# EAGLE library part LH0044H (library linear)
OP AMP

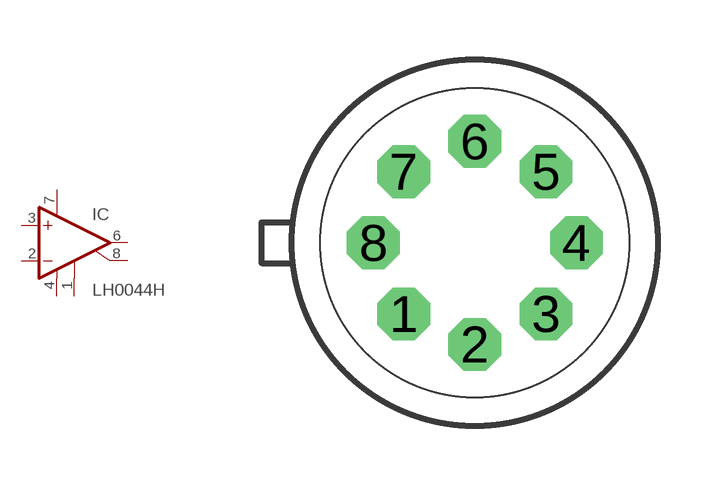
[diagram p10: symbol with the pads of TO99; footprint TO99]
Designator prefix IC

## LH0044H  [TO99]
1  CMP1  pas
2  -IN  in
3  +IN  in
4  V-  pwr
6  OUT  out
7  V+  pwr
8  CMP2  pas

## Footprint TO99 (pad centres in mm)
Metal Can Package
drill 0.813 octagon: 1 -1.778,-1.778; 2 0,-2.54; 3 1.778,-1.778; 4 2.54,0; 5 1.778,1.778; 6 0,2.54; 7 -1.778,1.778; 8 -2.54,0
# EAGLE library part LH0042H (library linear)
OP AMP

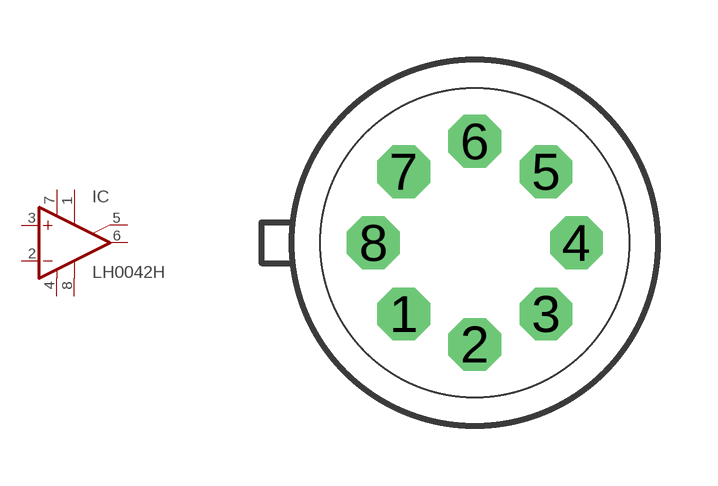
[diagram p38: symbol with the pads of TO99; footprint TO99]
Designator prefix IC

## LH0042H  [TO99]
1  ON1  pas
2  -IN  in
3  +IN  in
4  V-  pwr
5  ON2  pas
6  OUT  out
7  V+  pwr
8  OPT  pas

## Footprint TO99 (pad centres in mm)
Metal Can Package
drill 0.813 octagon: 1 -1.778,-1.778; 2 0,-2.54; 3 1.778,-1.778; 4 2.54,0; 5 1.778,1.778; 6 0,2.54; 7 -1.778,1.778; 8 -2.54,0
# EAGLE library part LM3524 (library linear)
Regulating Pulse Width Modulator LM2524D/LM3524D Source: http://cache.national.com/ds/LM/LM2524D.pdf

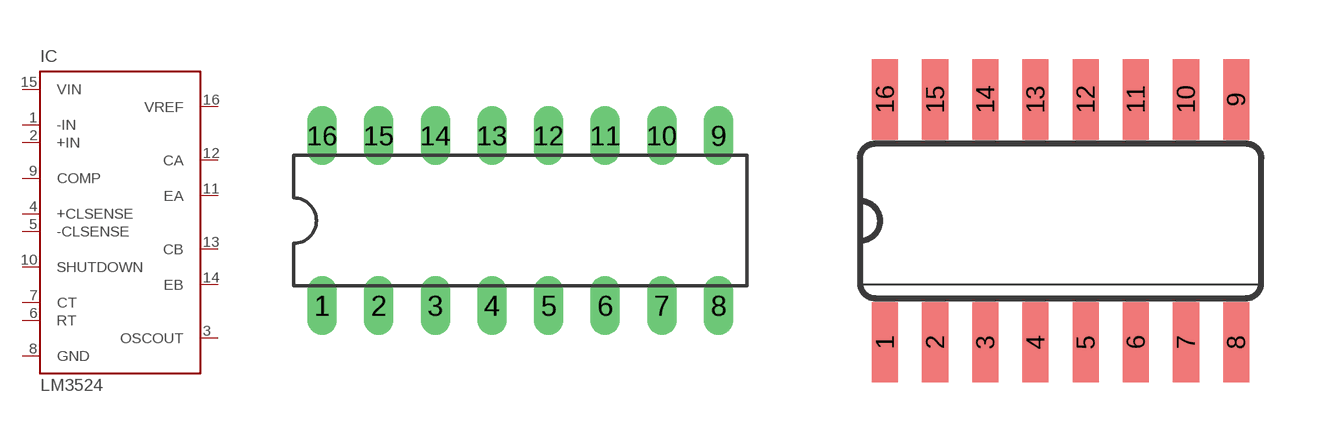
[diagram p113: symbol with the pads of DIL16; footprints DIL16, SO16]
Designator prefix IC

## LM3524N  [DIL16]
1  -IN  in
2  +IN  in
3  OSCOUT  out
4  +CLSENSE  in
5  -CLSENSE  in
6  RT  in
7  CT  in
8  GND  pwr
9  COMP  in
10  SHUTDOWN  in
11  EA  pas
12  CA  pas
13  CB  pas
14  EB  pas
15  VIN  in
16  VREF  pas

## LM3524D  [SO16]
Pads as for DIL16

## Footprint DIL16 (pad centres in mm)
Dual In Line Package
drill 0.813 long: 1 -8.89,-3.81; 2 -6.35,-3.81; 3 -3.81,-3.81; 4 -1.27,-3.81; 5 1.27,-3.81; 6 3.81,-3.81; 7 6.35,-3.81; 8 8.89,-3.81; 9 8.89,3.81; 10 6.35,3.81; 11 3.81,3.81; 12 1.27,3.81; 13 -1.27,3.81; 14 -3.81,3.81; 15 -6.35,3.81; 16 -8.89,3.81

## Footprint SO16 (pad centres in mm)
Small Outline Package 16
smd 0.66 x 2.032: 1 -4.445,-3.073; 2 -3.175,-3.073; 3 -1.905,-3.073; 4 -0.635,-3.073; 5 0.635,-3.073; 6 1.905,-3.073; 7 3.175,-3.073; 8 4.445,-3.073; 9 4.445,3.073; 10 3.175,3.073; 11 1.905,3.073; 12 0.635,3.073; 13 -0.635,3.073; 14 -1.905,3.073; 15 -3.175,3.073; 16 -4.445,3.073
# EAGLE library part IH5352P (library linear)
CMOS SWITCH

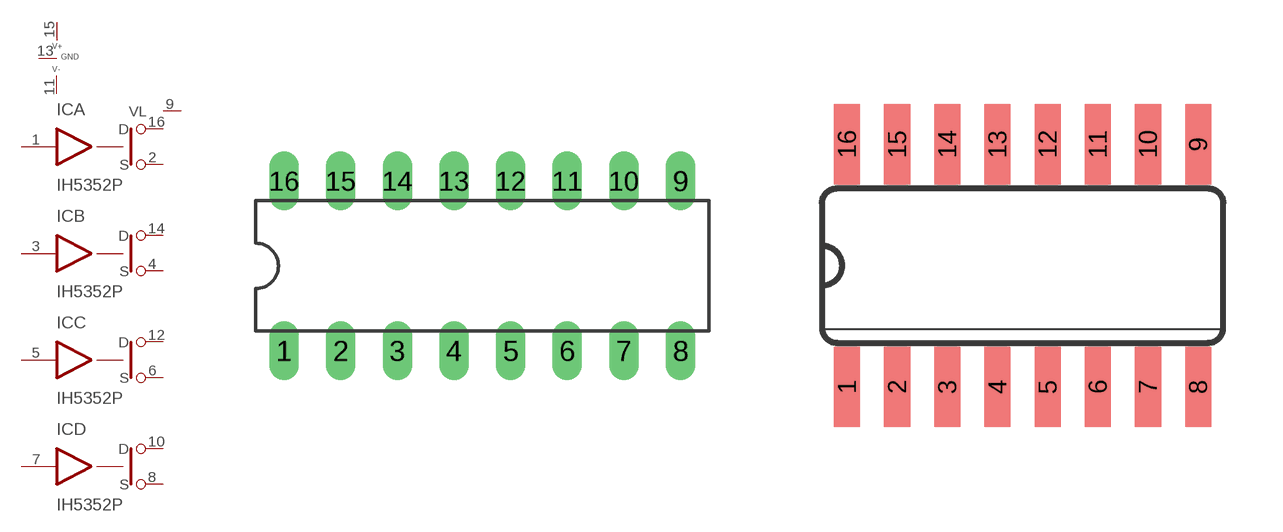
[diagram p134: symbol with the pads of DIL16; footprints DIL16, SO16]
Designator prefix IC; gates A=SWSPSTNI B=SWSPSTNI C=SWSPSTNI D=SWSPSTNI P=PWR+-GSS VL=VL_PIN

## IH5352PP  [DIL16]
1  A:IN  in
2  A:S
3  B:IN  in
4  B:S
5  C:IN  in
6  C:S
7  D:IN  in
8  D:S
9  VL:VL  in
10  D:D
11  P:V-  pwr
12  C:D
13  P:GND  pwr
14  B:D
15  P:V+  pwr
16  A:D

## IH5352PD  [SO16]
Pads as for DIL16

## Footprint DIL16 (pad centres in mm)
Dual In Line Package
drill 0.813 long: 1 -8.89,-3.81; 2 -6.35,-3.81; 3 -3.81,-3.81; 4 -1.27,-3.81; 5 1.27,-3.81; 6 3.81,-3.81; 7 6.35,-3.81; 8 8.89,-3.81; 9 8.89,3.81; 10 6.35,3.81; 11 3.81,3.81; 12 1.27,3.81; 13 -1.27,3.81; 14 -3.81,3.81; 15 -6.35,3.81; 16 -8.89,3.81

## Footprint SO16 (pad centres in mm)
Small Outline Package 16
smd 0.66 x 2.032: 1 -4.445,-3.073; 2 -3.175,-3.073; 3 -1.905,-3.073; 4 -0.635,-3.073; 5 0.635,-3.073; 6 1.905,-3.073; 7 3.175,-3.073; 8 4.445,-3.073; 9 4.445,3.073; 10 3.175,3.073; 11 1.905,3.073; 12 0.635,3.073; 13 -0.635,3.073; 14 -1.905,3.073; 15 -3.175,3.073; 16 -4.445,3.073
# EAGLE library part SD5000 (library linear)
DMOS SWITCH

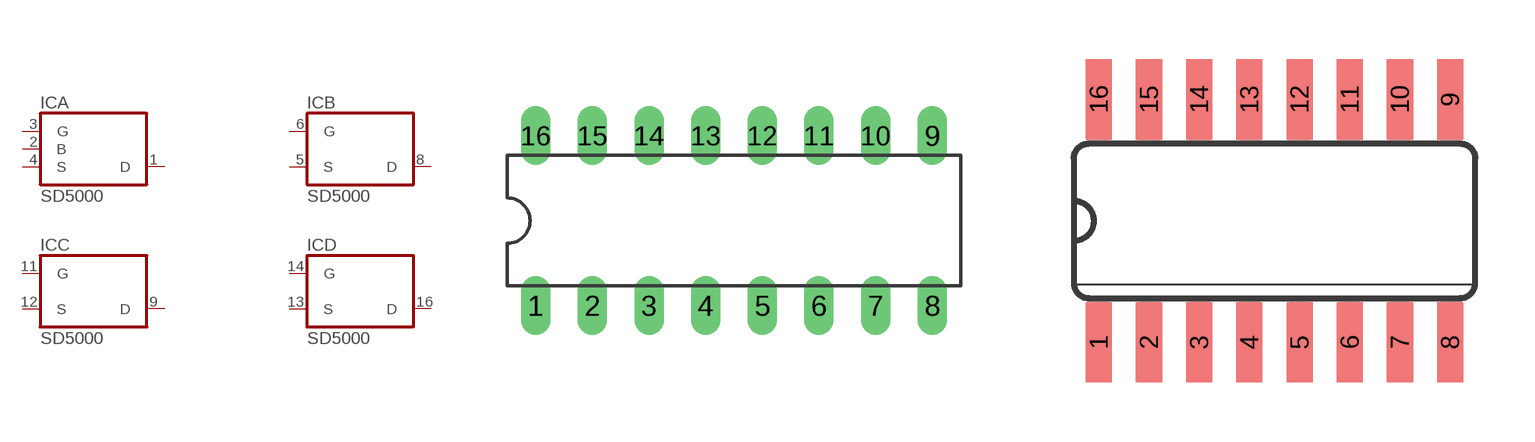
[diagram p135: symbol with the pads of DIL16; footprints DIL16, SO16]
Designator prefix IC; gates A=SD5000 P=SD5000/B B=SD5000 C=SD5000 D=SD5000

## SD5000N  [DIL16]
1  A:D  out
2  P:B  pwr
3  A:G  in
4  A:S  in
5  B:S  in
6  B:G  in
8  B:D  out
9  C:D  out
11  C:G  in
12  C:S  in
13  D:S  in
14  D:G  in
16  D:D  out

## SD5000D  [SO16]
Pads as for DIL16

## Footprint DIL16 (pad centres in mm)
Dual In Line Package
drill 0.813 long: 1 -8.89,-3.81; 2 -6.35,-3.81; 3 -3.81,-3.81; 4 -1.27,-3.81; 5 1.27,-3.81; 6 3.81,-3.81; 7 6.35,-3.81; 8 8.89,-3.81; 9 8.89,3.81; 10 6.35,3.81; 11 3.81,3.81; 12 1.27,3.81; 13 -1.27,3.81; 14 -3.81,3.81; 15 -6.35,3.81; 16 -8.89,3.81

## Footprint SO16 (pad centres in mm)
Small Outline Package 16
smd 0.66 x 2.032: 1 -4.445,-3.073; 2 -3.175,-3.073; 3 -1.905,-3.073; 4 -0.635,-3.073; 5 0.635,-3.073; 6 1.905,-3.073; 7 3.175,-3.073; 8 4.445,-3.073; 9 4.445,3.073; 10 3.175,3.073; 11 1.905,3.073; 12 0.635,3.073; 13 -0.635,3.073; 14 -1.905,3.073; 15 -3.175,3.073; 16 -4.445,3.073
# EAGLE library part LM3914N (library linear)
LED DRIVER senses analog voltage levels and drives 10 LEDs

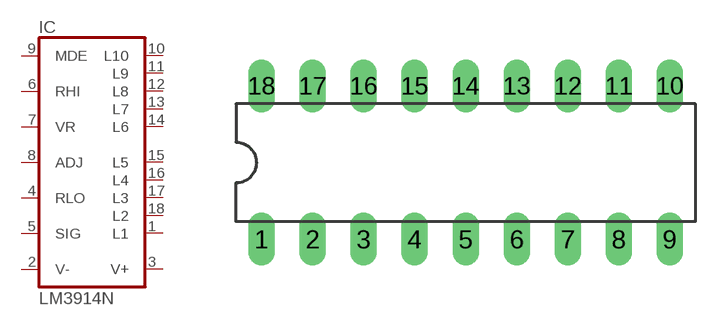
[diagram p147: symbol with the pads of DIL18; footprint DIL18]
Designator prefix IC

## LM3914N  [DIL18]
1  L1  out
2  V-  pwr
3  V+  pwr
4  RLO  in
5  SIG  in
6  RHI  in
7  VR  out
8  ADJ  in
9  MDE  in
10  L10  out
11  L9  out
12  L8  out
13  L7  out
14  L6  out
15  L5  out
16  L4  out
17  L3  out
18  L2  out

## Footprint DIL18 (pad centres in mm)
Dual In Line Package
drill 0.813 long: 1 -10.16,-3.81; 2 -7.62,-3.81; 3 -5.08,-3.81; 4 -2.54,-3.81; 5 0,-3.81; 6 2.54,-3.81; 7 5.08,-3.81; 8 7.62,-3.81; 9 10.16,-3.81; 10 10.16,3.81; 11 7.62,3.81; 12 5.08,3.81; 13 2.54,3.81; 14 0,3.81; 15 -2.54,3.81; 16 -5.08,3.81; 17 -7.62,3.81; 18 -10.16,3.81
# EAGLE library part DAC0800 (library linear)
8-bit DIGITAL/ANALOG CONVERTER

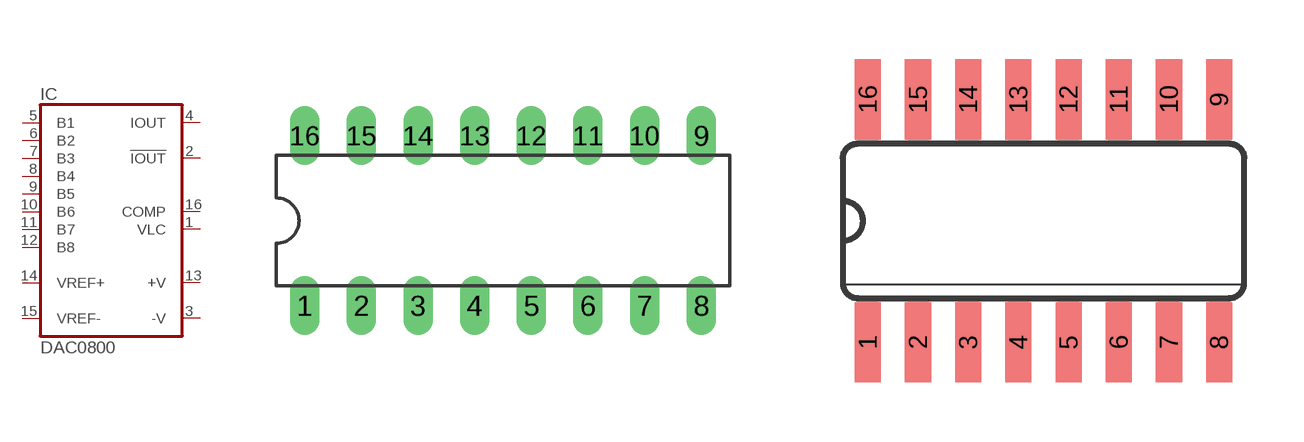
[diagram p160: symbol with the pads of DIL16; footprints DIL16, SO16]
Designator prefix IC

## DAC0800N  [DIL16]
1  VLC  in
2  !IOUT  out
3  -V  pwr
4  IOUT  out
5  B1  in
6  B2  in
7  B3  in
8  B4  in
9  B5  in
10  B6  in
11  B7  in
12  B8  in
13  +V  pwr
14  VREF+  in
15  VREF-  in
16  COMP  in

## DAC0800D  [SO16]
Pads as for DIL16

## Footprint DIL16 (pad centres in mm)
Dual In Line Package
drill 0.813 long: 1 -8.89,-3.81; 2 -6.35,-3.81; 3 -3.81,-3.81; 4 -1.27,-3.81; 5 1.27,-3.81; 6 3.81,-3.81; 7 6.35,-3.81; 8 8.89,-3.81; 9 8.89,3.81; 10 6.35,3.81; 11 3.81,3.81; 12 1.27,3.81; 13 -1.27,3.81; 14 -3.81,3.81; 15 -6.35,3.81; 16 -8.89,3.81

## Footprint SO16 (pad centres in mm)
Small Outline Package 16
smd 0.66 x 2.032: 1 -4.445,-3.073; 2 -3.175,-3.073; 3 -1.905,-3.073; 4 -0.635,-3.073; 5 0.635,-3.073; 6 1.905,-3.073; 7 3.175,-3.073; 8 4.445,-3.073; 9 4.445,3.073; 10 3.175,3.073; 11 1.905,3.073; 12 0.635,3.073; 13 -0.635,3.073; 14 -1.905,3.073; 15 -3.175,3.073; 16 -4.445,3.073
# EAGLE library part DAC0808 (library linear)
8-bit DIGITAL/ANALOG CONVERTER Source: http://www.national.com/ds/DA/DAC0808.pdf

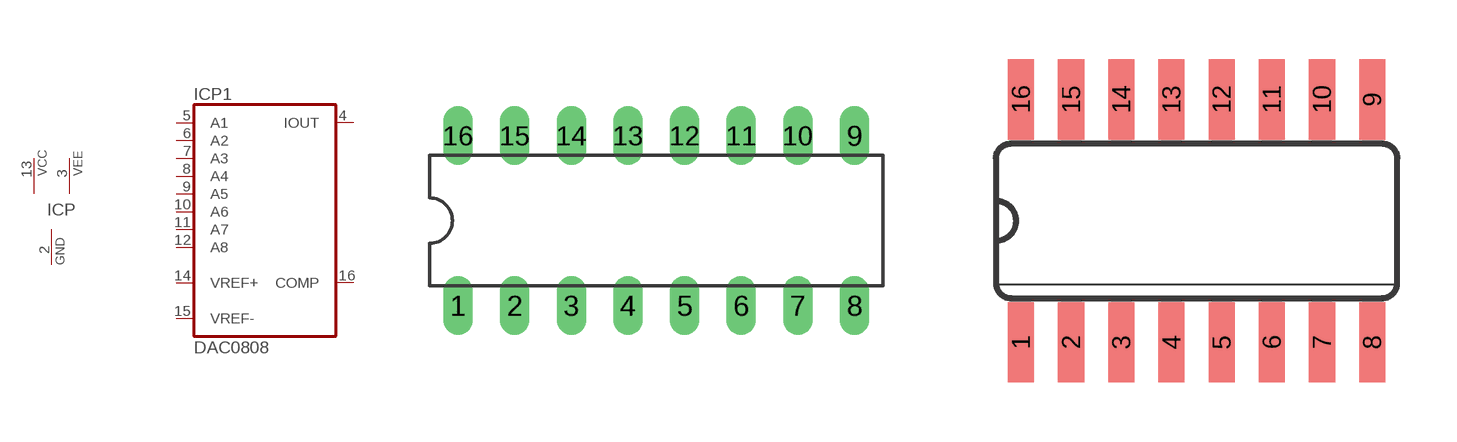
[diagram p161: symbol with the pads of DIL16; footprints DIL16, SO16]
Designator prefix IC; gates P=2PWRGND P1=DAC0808

## DAC0808N  [DIL16]
2  P:GND  pwr
3  P:VEE  pwr
4  P1:IOUT  out
5  P1:A1  in
6  P1:A2  in
7  P1:A3  in
8  P1:A4  in
9  P1:A5  in
10  P1:A6  in
11  P1:A7  in
12  P1:A8  in
13  P:VCC  pwr
14  P1:VREF+  in
15  P1:VREF-  in
16  P1:COMP  in

## DAC0808D  [SO16]
1  P:VCC  pwr
2  P1:VREF+  in
3  P1:VREF-  in
4  P1:COMP  in
6  P:GND  pwr
7  P:VEE  pwr
8  P1:IOUT  out
9  P1:A1  in
10  P1:A2  in
11  P1:A3  in
12  P1:A4  in
13  P1:A5  in
14  P1:A6  in
15  P1:A7  in
16  P1:A8  in

## Footprint DIL16 (pad centres in mm)
Dual In Line Package
drill 0.813 long: 1 -8.89,-3.81; 2 -6.35,-3.81; 3 -3.81,-3.81; 4 -1.27,-3.81; 5 1.27,-3.81; 6 3.81,-3.81; 7 6.35,-3.81; 8 8.89,-3.81; 9 8.89,3.81; 10 6.35,3.81; 11 3.81,3.81; 12 1.27,3.81; 13 -1.27,3.81; 14 -3.81,3.81; 15 -6.35,3.81; 16 -8.89,3.81

## Footprint SO16 (pad centres in mm)
Small Outline Package 16
smd 0.66 x 2.032: 1 -4.445,-3.073; 2 -3.175,-3.073; 3 -1.905,-3.073; 4 -0.635,-3.073; 5 0.635,-3.073; 6 1.905,-3.073; 7 3.175,-3.073; 8 4.445,-3.073; 9 4.445,3.073; 10 3.175,3.073; 11 1.905,3.073; 12 0.635,3.073; 13 -0.635,3.073; 14 -1.905,3.073; 15 -3.175,3.073; 16 -4.445,3.073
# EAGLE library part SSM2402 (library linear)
ANALOG SWITCH

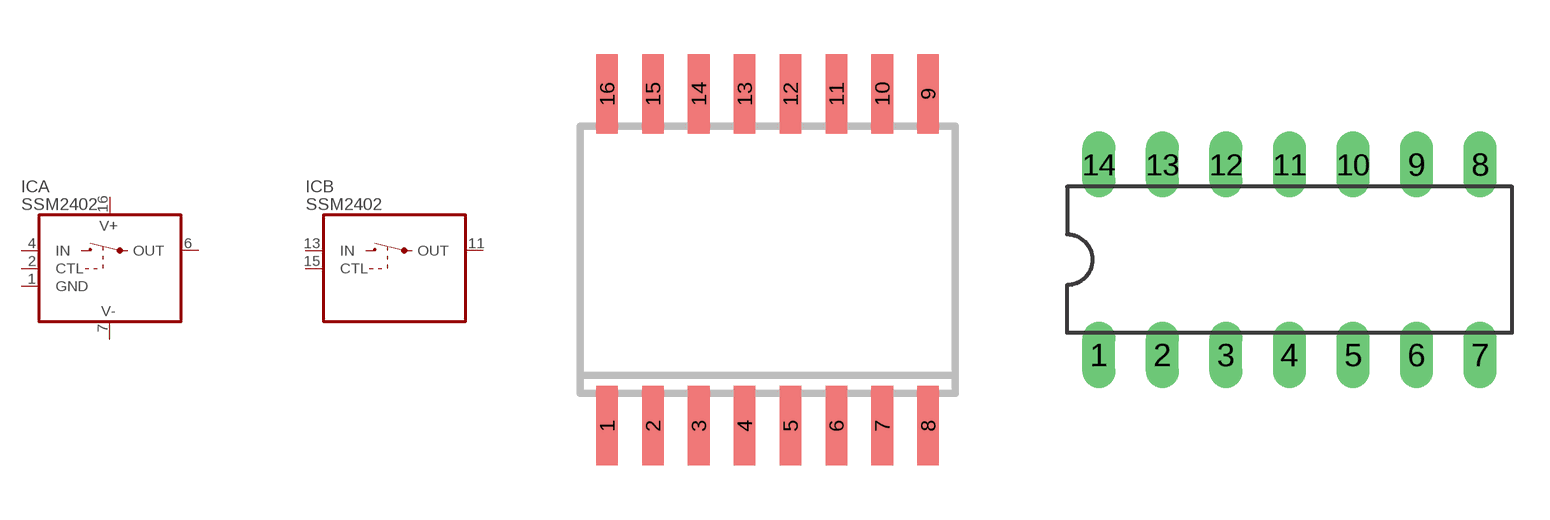
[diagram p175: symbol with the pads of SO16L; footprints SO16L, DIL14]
Designator prefix IC; gates A=SSM2402 B=SSM2402 P=PWR+-GR

## SSM2402S  [SO16L]
1  P:GND  pwr
2  A:CTL  in
4  A:IN  in
6  A:OUT  out
7  P:V-  pwr
11  B:OUT  out
13  B:IN  in
15  B:CTL  in
16  P:V+  pwr

## SSM2402P  [DIL14]
1  P:GND  pwr
2  A:CTL  in
4  A:IN  in
6  A:OUT  out
7  P:V-  pwr
9  B:OUT  out
11  B:IN  in
13  B:CTL  in
14  P:V+  pwr

## Footprint SO16L (pad centres in mm)
Small Outline Package 16 large
smd 0.6 x 2.2: 1 -4.445,-4.6; 2 -3.175,-4.6; 3 -1.905,-4.6; 4 -0.635,-4.6; 5 0.635,-4.6; 6 1.905,-4.6; 7 3.175,-4.6; 8 4.445,-4.6; 9 4.445,4.6; 10 3.175,4.6; 11 1.905,4.6; 12 0.635,4.6; 13 -0.635,4.6; 14 -1.905,4.6; 15 -3.175,4.6; 16 -4.445,4.6

## Footprint DIL14 (pad centres in mm)
Dual In Line Package
drill 0.813 long: 1 -7.62,-3.81; 2 -5.08,-3.81; 3 -2.54,-3.81; 4 0,-3.81; 5 2.54,-3.81; 6 5.08,-3.81; 7 7.62,-3.81; 8 7.62,3.81; 9 5.08,3.81; 10 2.54,3.81; 11 0,3.81; 12 -2.54,3.81; 13 -5.08,3.81; 14 -7.62,3.81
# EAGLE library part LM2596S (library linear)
STEP-DOWN VOLTAGE REGULATOR

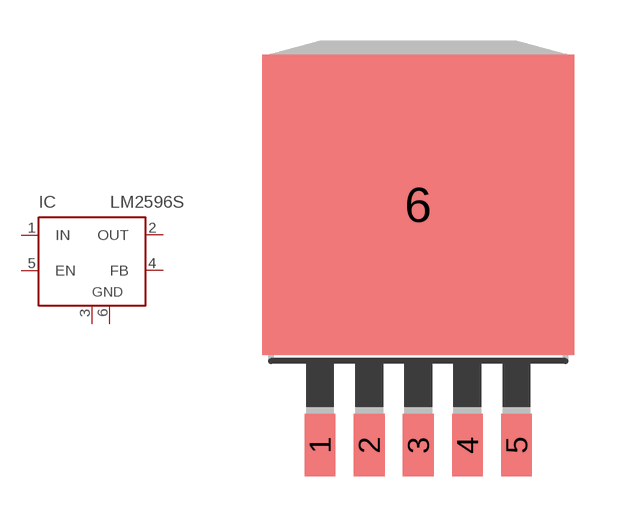
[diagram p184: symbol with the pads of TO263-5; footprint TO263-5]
Designator prefix IC

## LM2596S  [TO263-5]
1  IN  in
2  OUT  out
3  GND  pwr
4  FB  in
5  EN  in
6  GND  pwr

## Footprint TO263-5 (pad centres in mm)
TO-263
smd 1.067 x 2.159: 1 -3.404,-5.791; 2 -1.702,-5.791; 3 0,-5.791; 4 1.702,-5.791; 5 3.404,-5.791
smd 10.8 x 10.41: 6 0,2.54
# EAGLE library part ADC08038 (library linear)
A/D CONVERTER

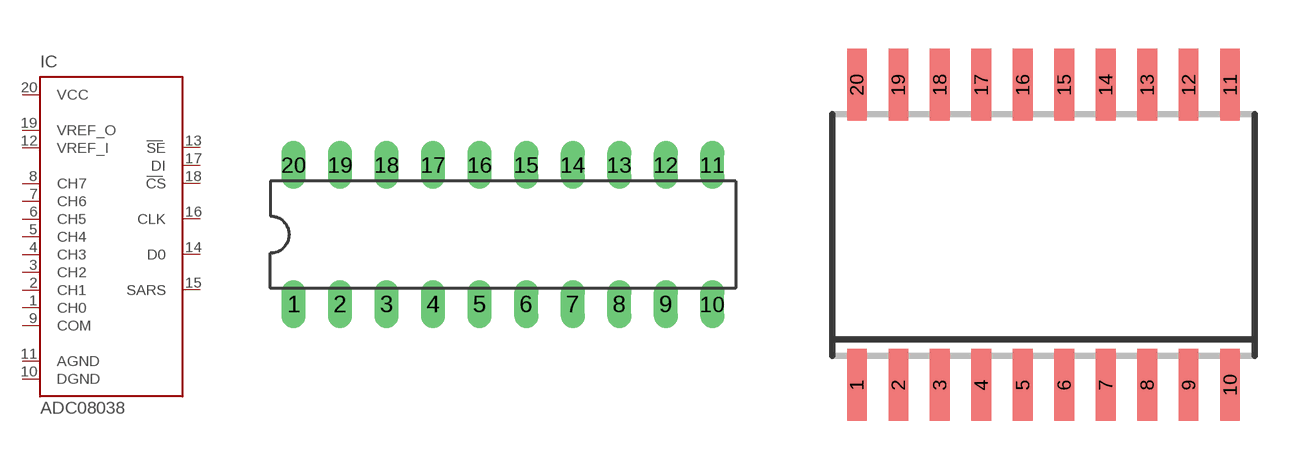
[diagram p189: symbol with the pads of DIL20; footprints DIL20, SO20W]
Designator prefix IC

## ADC08038N  [DIL20]
1  CH0  in
2  CH1  in
3  CH2  in
4  CH3  in
5  CH4  in
6  CH5  in
7  CH6  in
8  CH7  in
9  COM  in
10  DGND  pwr
11  AGND  pwr
12  VREF_I  in
13  SE  in
14  D0  hiz
15  SARS  out
16  CLK  in
17  DI  in
18  CS  in
19  VREF_O  out
20  VCC  pwr

## ADC08038D  [SO20W]
Pads as for DIL20

## Footprint DIL20 (pad centres in mm)
Dual In Line Package
drill 0.813 long: 1 -11.43,-3.81; 2 -8.89,-3.81; 3 -6.35,-3.81; 4 -3.81,-3.81; 5 -1.27,-3.81; 6 1.27,-3.81; 7 3.81,-3.81; 8 6.35,-3.81; 9 8.89,-3.81; 10 11.43,-3.81; 11 11.43,3.81; 12 8.89,3.81; 13 6.35,3.81; 14 3.81,3.81; 15 1.27,3.81; 16 -1.27,3.81; 17 -3.81,3.81; 18 -6.35,3.81; 19 -8.89,3.81; 20 -11.43,3.81

## Footprint SO20W (pad centres in mm)
Small Outline Package 20 wide
smd 0.6 x 2.2: 1 -5.715,-4.6; 2 -4.445,-4.6; 3 -3.175,-4.6; 4 -1.905,-4.6; 5 -0.635,-4.6; 6 0.635,-4.6; 7 1.905,-4.6; 8 3.175,-4.6; 9 4.445,-4.6; 10 5.715,-4.6; 11 5.715,4.6; 12 4.445,4.6; 13 3.175,4.6; 14 1.905,4.6; 15 0.635,4.6; 16 -0.635,4.6; 17 -1.905,4.6; 18 -3.175,4.6; 19 -4.445,4.6; 20 -5.715,4.6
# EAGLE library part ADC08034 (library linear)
A/D CONVERTER

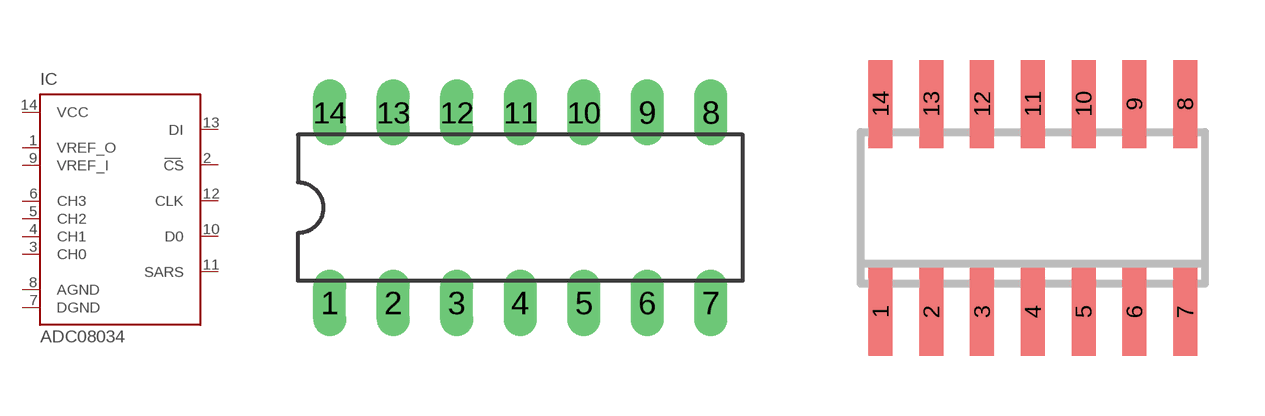
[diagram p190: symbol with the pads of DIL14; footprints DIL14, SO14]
Designator prefix IC

## ADC08034N  [DIL14]
1  VREF_O  out
2  CS  in
3  CH0  in
4  CH1  in
5  CH2  in
6  CH3  in
7  DGND  pwr
8  AGND  pwr
9  VREF_I  in
10  D0  hiz
11  SARS  out
12  CLK  in
13  DI  in
14  VCC  pwr

## ADC08034D  [SO14]
Pads as for DIL14

## Footprint DIL14 (pad centres in mm)
Dual In Line Package
drill 0.813 long: 1 -7.62,-3.81; 2 -5.08,-3.81; 3 -2.54,-3.81; 4 0,-3.81; 5 2.54,-3.81; 6 5.08,-3.81; 7 7.62,-3.81; 8 7.62,3.81; 9 5.08,3.81; 10 2.54,3.81; 11 0,3.81; 12 -2.54,3.81; 13 -5.08,3.81; 14 -7.62,3.81

## Footprint SO14 (pad centres in mm)
Small Outline Package 14
smd 0.6 x 2.2: 1 -3.81,-2.6; 2 -2.54,-2.6; 3 -1.27,-2.6; 4 0,-2.6; 5 1.27,-2.6; 6 2.54,-2.6; 7 3.81,-2.6; 8 3.81,2.6; 9 2.54,2.6; 10 1.27,2.6; 11 0,2.6; 12 -1.27,2.6; 13 -2.54,2.6; 14 -3.81,2.6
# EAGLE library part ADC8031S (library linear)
A/D CONVERTER

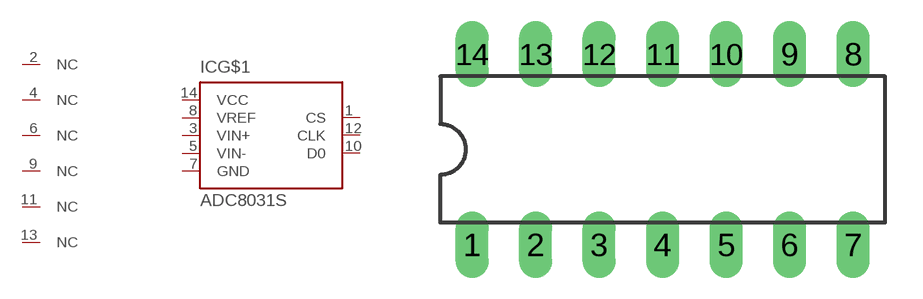
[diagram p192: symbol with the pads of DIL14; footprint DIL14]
Designator prefix IC; gates G$1=ADC08031 2=NC 4=NC 6=NC 9=NC 11=NC 13=NC

## ADC8031S  [DIL14]
1  G$1:CS  in
2  2:NC  nc
3  G$1:VIN+  in
4  4:NC  nc
5  G$1:VIN-  in
6  6:NC  nc
7  G$1:GND  pwr
8  G$1:VREF  in
9  9:NC  nc
10  G$1:D0  hiz
11  11:NC  nc
12  G$1:CLK  in
13  13:NC  nc
14  G$1:VCC  pwr

## Footprint DIL14 (pad centres in mm)
Dual In Line Package
drill 0.813 long: 1 -7.62,-3.81; 2 -5.08,-3.81; 3 -2.54,-3.81; 4 0,-3.81; 5 2.54,-3.81; 6 5.08,-3.81; 7 7.62,-3.81; 8 7.62,3.81; 9 5.08,3.81; 10 2.54,3.81; 11 0,3.81; 12 -2.54,3.81; 13 -5.08,3.81; 14 -7.62,3.81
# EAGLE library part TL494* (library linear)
SWITCHMODE Pulse Width Modulation Control Circuit NCV494B http://onsemi.com tl494-d.pdf

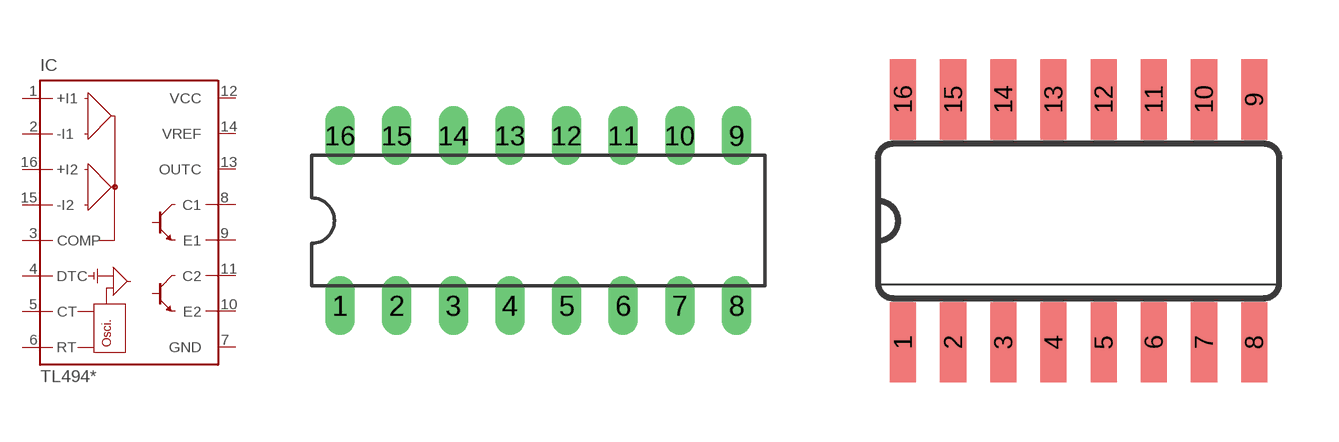
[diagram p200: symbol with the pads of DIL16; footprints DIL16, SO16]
Designator prefix IC

## TL494CN, TL494IN  [DIL16]
1  +I1  in
2  -I1  in
3  COMP  pas
4  DTC  in
5  CT  in
6  RT  in
7  GND  pwr
8  C1  pas
9  E1  pas
10  E2  pas
11  C2  pas
12  VCC  pwr
13  OUTC  out
14  VREF  in
15  -I2  in
16  +I2  in

## TL494BD, TL494CD  [SO16]
Pads as for DIL16

## Footprint DIL16 (pad centres in mm)
Dual In Line Package
drill 0.813 long: 1 -8.89,-3.81; 2 -6.35,-3.81; 3 -3.81,-3.81; 4 -1.27,-3.81; 5 1.27,-3.81; 6 3.81,-3.81; 7 6.35,-3.81; 8 8.89,-3.81; 9 8.89,3.81; 10 6.35,3.81; 11 3.81,3.81; 12 1.27,3.81; 13 -1.27,3.81; 14 -3.81,3.81; 15 -6.35,3.81; 16 -8.89,3.81

## Footprint SO16 (pad centres in mm)
Small Outline Package 16
smd 0.66 x 2.032: 1 -4.445,-3.073; 2 -3.175,-3.073; 3 -1.905,-3.073; 4 -0.635,-3.073; 5 0.635,-3.073; 6 1.905,-3.073; 7 3.175,-3.073; 8 4.445,-3.073; 9 4.445,3.073; 10 3.175,3.073; 11 1.905,3.073; 12 0.635,3.073; 13 -0.635,3.073; 14 -1.905,3.073; 15 -3.175,3.073; 16 -4.445,3.073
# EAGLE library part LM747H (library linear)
Dual Operational Amplifier Source: http://cache.national.com/ds/LM/LM747.pdf

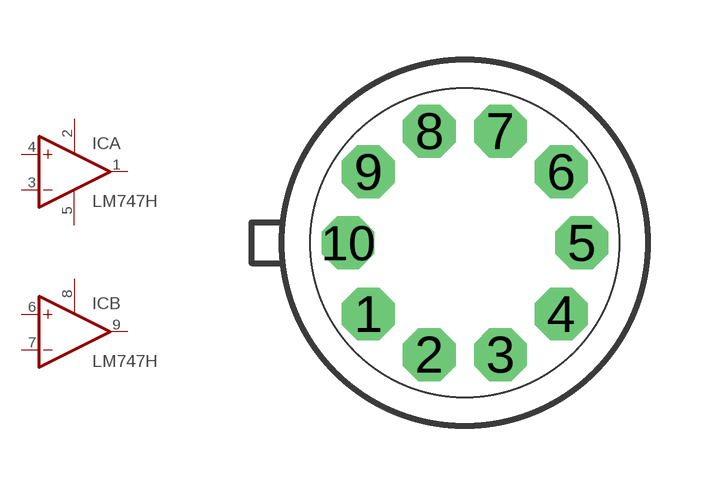
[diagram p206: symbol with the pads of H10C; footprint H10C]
Designator prefix IC; gates A=OPAMP+ B=OPAMP+ P=-V

## LM747H  [H10C]
1  A:OUT  out
2  A:V+  pwr
3  A:-IN  in
4  A:+IN  in
5  P:V-  pwr
6  B:+IN  in
7  B:-IN  in
8  B:V+  pwr
9  B:OUT  out

## Footprint H10C (pad centres in mm)
Metal Can Package National Semiconductor NS H10C Motorola 603-04 / 603C-01
drill 0.813 octagon: 1 -2.413,-1.778; 2 -0.889,-2.794; 3 0.889,-2.794; 4 2.413,-1.778; 5 2.921,0; 6 2.413,1.778; 7 0.889,2.794; 8 -0.889,2.794; 9 -2.413,1.778; 10 -2.921,0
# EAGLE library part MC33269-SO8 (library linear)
Adjustable Output Low Dropout Voltage Regulator 800 mA Source: http://www.onsemi.com/pub/Collateral/MC33269-D.PDF

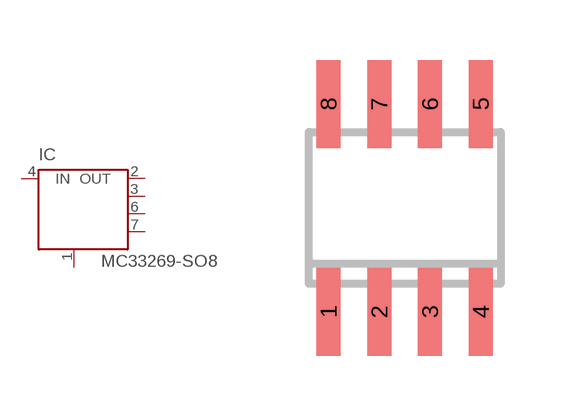
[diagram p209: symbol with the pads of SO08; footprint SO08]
Designator prefix IC

## MC33269-SO8  [SO08]
1  GND/ADJ  in
2  OUT  pas
3  OUT  pas
4  IN  in
6  OUT  pas
7  OUT  pas

## Footprint SO08 (pad centres in mm)
Small Outline Package 8 NS Package M08A
smd 0.6 x 2.2: 1 -1.905,-2.6; 2 -0.635,-2.6; 3 0.635,-2.6; 4 1.905,-2.6; 5 1.905,2.6; 6 0.635,2.6; 7 -0.635,2.6; 8 -1.905,2.6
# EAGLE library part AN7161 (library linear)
BTL High Audio Power Amplifier AN7161NFP Source: http://www.steren.com.mx/diagramas/uploads/an7161.pdf

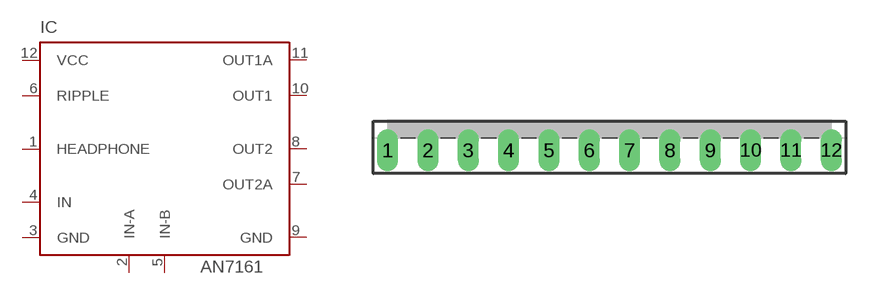
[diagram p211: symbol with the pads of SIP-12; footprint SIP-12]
Designator prefix IC

## AN7161  [SIP-12]
1  HEADPHONE  in
2  IN-A  pas
3  GND  pwr
4  IN  in
5  IN-B  pas
6  RIPPLE  in
7  OUT2A  in
8  OUT2  out
9  GND  pwr
10  OUT1  out
11  OUT1A  in
12  VCC  pwr

## Footprint SIP-12 (pad centres in mm)
12-Lead SIL Platic Package with Fin (12-SIP-FP) Source: http://www.steren.com.mx/diagramas/uploads/an7161.pdf
drill 0.8 pad 1.27 long: 1 -13.97,0; 2 -11.43,0; 3 -8.89,0; 4 -6.35,0; 5 -3.81,0; 6 -1.27,0; 7 1.27,0; 8 3.81,0; 9 6.35,0; 10 8.89,0; 11 11.43,0; 12 13.97,0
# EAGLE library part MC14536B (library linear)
Programmable Timer Source: http://www.onsemi.com/pub/Collateral/MC14536B-D.PDF

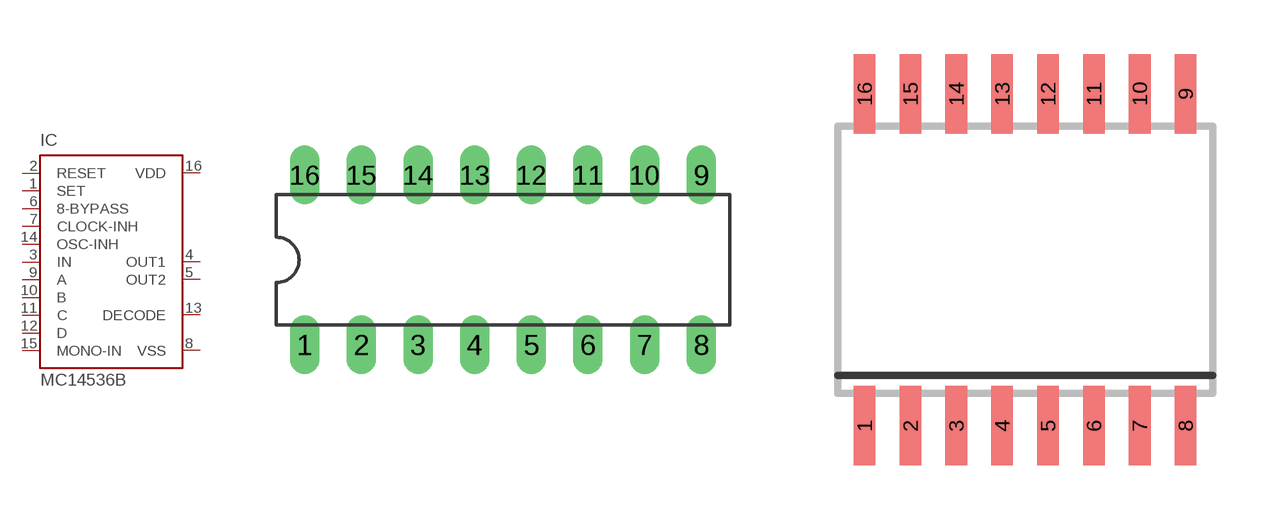
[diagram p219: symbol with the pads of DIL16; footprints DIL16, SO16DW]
Designator prefix IC

## MC14536BCP  [DIL16]
1  SET  in
2  RESET  in
3  IN  in
4  OUT1  out
5  OUT2  out
6  8-BYPASS  in
7  CLOCK-INH  in
8  VSS  pwr
9  A  in
10  B  in
11  C  in
12  D  in
13  DECODE  out
14  OSC-INH  in
15  MONO-IN  in
16  VDD  pwr

## MC14536BDW  [SO16DW]
Pads as for DIL16

## MC14536BF  [SO16-F]
Pads as for DIL16

## Footprint DIL16 (pad centres in mm)
Dual In Line Package
drill 0.813 long: 1 -8.89,-3.81; 2 -6.35,-3.81; 3 -3.81,-3.81; 4 -1.27,-3.81; 5 1.27,-3.81; 6 3.81,-3.81; 7 6.35,-3.81; 8 8.89,-3.81; 9 8.89,3.81; 10 6.35,3.81; 11 3.81,3.81; 12 1.27,3.81; 13 -1.27,3.81; 14 -3.81,3.81; 15 -6.35,3.81; 16 -8.89,3.81

## Footprint SO16DW (pad centres in mm)
SOIC 16 DW SUFFIX PLASTIC SOIC PACKAGE CASE 751G-03 ISSUE B http://www.onsemi.com/pub/Collateral/MC14536B-D.PDF
smd 0.6 x 2.2: 1 -4.445,-4.6; 2 -3.175,-4.6; 3 -1.905,-4.6; 4 -0.635,-4.6; 5 0.635,-4.6; 6 1.905,-4.6; 7 3.175,-4.6; 8 4.445,-4.6; 9 4.445,4.6; 10 3.175,4.6; 11 1.905,4.6; 12 0.635,4.6; 13 -0.635,4.6; 14 -1.905,4.6; 15 -3.175,4.6; 16 -4.445,4.6

## Footprint SO16-F (pad centres in mm)
SOEIAJ-16 F SUFFIX PLASTIC EIAJ SOIC PACKAGE CASE 966-01 ISSUE O Source: http://www.onsemi.com/pub/Collateral/MC14536B-D.PDF
smd 0.66 x 2.032: 1 -4.445,-3.748; 2 -3.175,-3.748; 3 -1.905,-3.748; 4 -0.635,-3.748; 5 0.635,-3.748; 6 1.905,-3.748; 7 3.175,-3.748; 8 4.445,-3.748; 9 4.445,3.748; 10 3.175,3.748; 11 1.905,3.748; 12 0.635,3.748; 13 -0.635,3.748; 14 -1.905,3.748; 15 -3.175,3.748; 16 -4.445,3.748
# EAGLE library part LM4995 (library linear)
1.3 Watt Audio Power Amplifier BOOMER Audio Power Amplifier Series Source: http://www.national.com .. LM4995.pdf

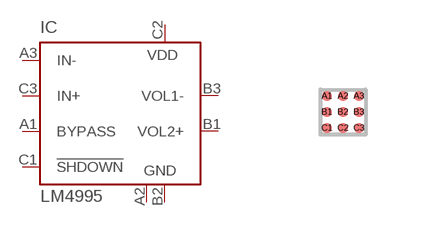
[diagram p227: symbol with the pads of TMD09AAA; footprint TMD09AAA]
Designator prefix IC

## LM4995  [TMD09AAA]
A1  BYPASS  pas
A2  GND  pwr
A3  IN-  in
B1  VOL2+  out
B2  GND  pwr
B3  VOL1-  out
C1  !SHDOWN  in
C2  VDD  pwr
C3  IN+  in

## Footprint TMD09AAA (pad centres in mm)
THIN MICRO SMD, 9 BUMP, 0.4mm PITCH 1.22 x 1.22 x 0.60mm body size Source: http://www.national.com/packaging/mkt/tmd09xxx.pdf
smd 0.24 x 0.24: A1 -0.4,0.4; A2 0,0.4; A3 0.4,0.4; B1 -0.4,0; B2 0,0; B3 0.4,0; C1 -0.4,-0.4; C2 0,-0.4; C3 0.4,-0.4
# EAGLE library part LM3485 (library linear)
Hysteretic PFET Buck Controller Source: http://cache.national.com/ds/LM/LM3485.pdf

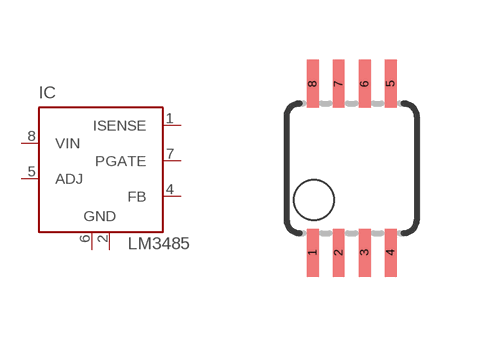
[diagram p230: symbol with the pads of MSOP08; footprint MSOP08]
Designator prefix IC

## LM3485  [MSOP08]
1  ISENSE  in
2  GND  pwr
4  FB  in
5  ADJ  in
6  GND  pwr
7  PGATE  out
8  VIN  in

## Footprint MSOP08 (pad centres in mm)
Mini Small Outline Package
smd 0.3 x 1.2: 1 -0.976,-2.113; 2 -0.326,-2.113; 3 0.324,-2.113; 4 0.974,-2.113; 5 0.974,2.112; 6 0.324,2.112; 7 -0.326,2.112; 8 -0.976,2.112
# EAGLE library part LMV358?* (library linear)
Dual General Purpose, Low Voltage, Rail-to-Rail Output Operational Amplifiers Source: http://www.national.com/mpf/LM/LMV321.html http://www.national.com/dt/lmv_qual.pdf

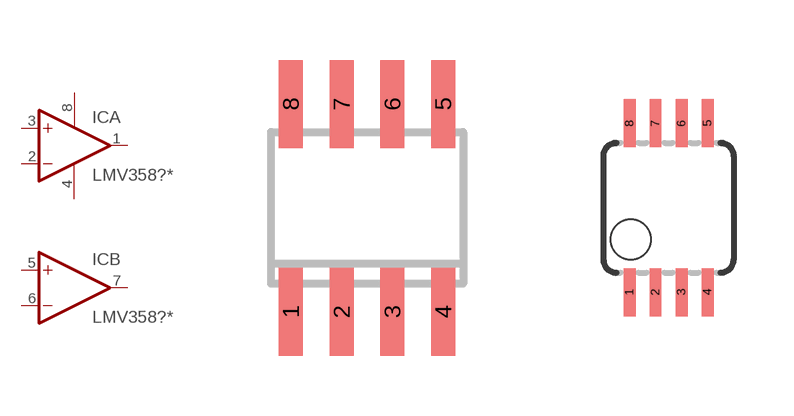
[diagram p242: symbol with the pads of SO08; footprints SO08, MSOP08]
Designator prefix IC; gates A=OPAMP B=OPAMP P=PWR+-

## LMV358M, LMV358MX  [SO08]
1  A:OUT  out
2  A:-IN  in
3  A:+IN  in
4  P:V-  pwr
5  B:+IN  in
6  B:-IN  in
7  B:OUT  out
8  P:V+  pwr

## LMV358MM, LMV358MMX  [MSOP08]
Pads as for SO08

## Footprint SO08 (pad centres in mm)
Small Outline Package 8 NS Package M08A
smd 0.6 x 2.2: 1 -1.905,-2.6; 2 -0.635,-2.6; 3 0.635,-2.6; 4 1.905,-2.6; 5 1.905,2.6; 6 0.635,2.6; 7 -0.635,2.6; 8 -1.905,2.6

## Footprint MSOP08 (pad centres in mm)
Mini Small Outline Package
smd 0.3 x 1.2: 1 -0.976,-2.113; 2 -0.326,-2.113; 3 0.324,-2.113; 4 0.974,-2.113; 5 0.974,2.112; 6 0.324,2.112; 7 -0.326,2.112; 8 -0.976,2.112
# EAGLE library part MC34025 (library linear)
High Speed Double-Ended PWM Controller Source: http://www.onsemi.com/pub/Collateral/MC34025-D.PDF

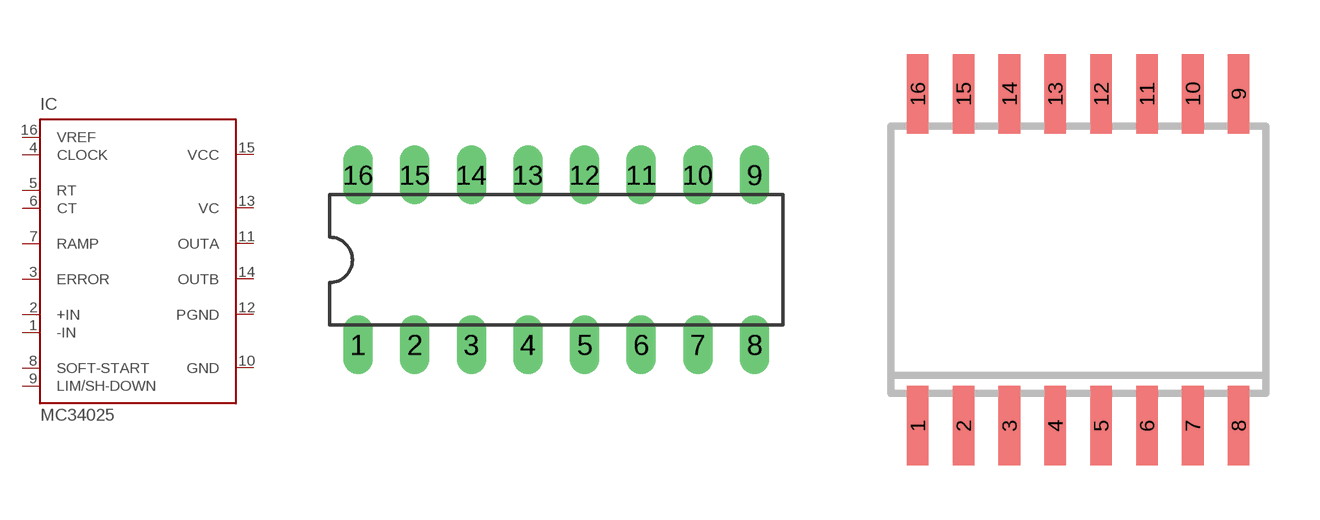
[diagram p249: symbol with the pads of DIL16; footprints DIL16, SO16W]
Designator prefix IC

## MC34025P  [DIL16]
1  -IN  in
2  +IN  in
3  ERROR  out
4  CLOCK  in
5  RT  in
6  CT  in
7  RAMP  in
8  SOFT-START  in
9  LIM/SH-DOWN  in
10  GND  pwr
11  OUTA  out
12  PGND  pwr
13  VC  pwr
14  OUTB  out
15  VCC  pwr
16  VREF  in

## MC34025DW  [SO16W]
Pads as for DIL16

## Footprint DIL16 (pad centres in mm)
Dual In Line Package
drill 0.813 long: 1 -8.89,-3.81; 2 -6.35,-3.81; 3 -3.81,-3.81; 4 -1.27,-3.81; 5 1.27,-3.81; 6 3.81,-3.81; 7 6.35,-3.81; 8 8.89,-3.81; 9 8.89,3.81; 10 6.35,3.81; 11 3.81,3.81; 12 1.27,3.81; 13 -1.27,3.81; 14 -3.81,3.81; 15 -6.35,3.81; 16 -8.89,3.81

## Footprint SO16W (pad centres in mm)
SMALL OUTLINE INTEGRATED CIRCUIT wide body 7.5 mm/JEDEC MS-013AA
smd 0.6 x 2.2: 1 -4.445,-4.6; 2 -3.175,-4.6; 3 -1.905,-4.6; 4 -0.635,-4.6; 5 0.635,-4.6; 6 1.905,-4.6; 7 3.175,-4.6; 8 4.445,-4.6; 9 4.445,4.6; 10 3.175,4.6; 11 1.905,4.6; 12 0.635,4.6; 13 -0.635,4.6; 14 -1.905,4.6; 15 -3.175,4.6; 16 -4.445,4.6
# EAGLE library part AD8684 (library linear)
Quad Low Power, High Speed JFET Operational Amplifiers Source: http://www.analog.com/UploadedFiles/Data_Sheets/AD8682_8684.pdf

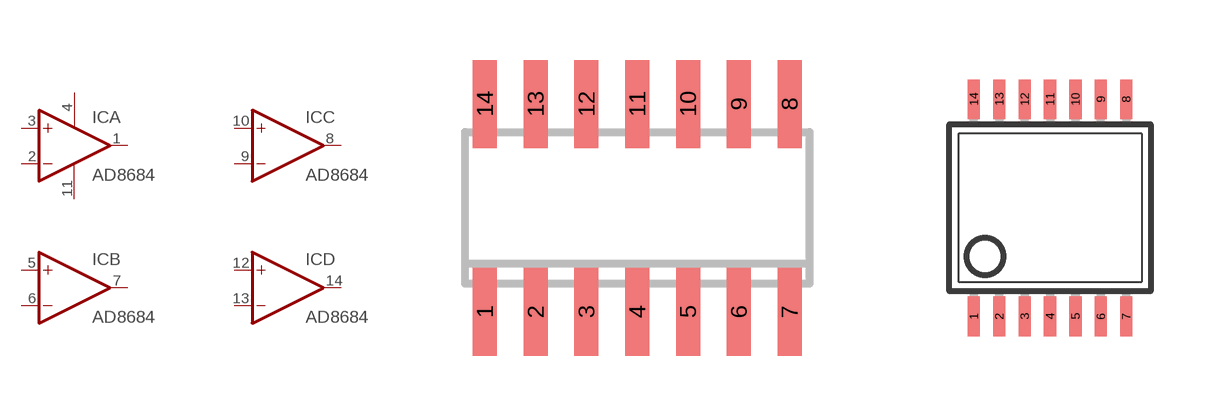
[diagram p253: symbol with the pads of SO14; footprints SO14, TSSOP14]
Designator prefix IC; gates A=OPAMP B=OPAMP C=OPAMP D=OPAMP P=PWR+-

## AD8684R  [SO14]
1  A:OUT  out
2  A:-IN  in
3  A:+IN  in
4  P:V+  pwr
5  B:+IN  in
6  B:-IN  in
7  B:OUT  out
8  C:OUT  out
9  C:-IN  in
10  C:+IN  in
11  P:V-  pwr
12  D:+IN  in
13  D:-IN  in
14  D:OUT  out

## AD8684RU  [TSSOP14]
Pads as for SO14

## Footprint SO14 (pad centres in mm)
Small Outline Package 14
smd 0.6 x 2.2: 1 -3.81,-2.6; 2 -2.54,-2.6; 3 -1.27,-2.6; 4 0,-2.6; 5 1.27,-2.6; 6 2.54,-2.6; 7 3.81,-2.6; 8 3.81,2.6; 9 2.54,2.6; 10 1.27,2.6; 11 0,2.6; 12 -1.27,2.6; 13 -2.54,2.6; 14 -3.81,2.6

## Footprint TSSOP14 (pad centres in mm)
Thin Shrink Small Outline Plastic 14
smd 0.305 x 0.991: 1 -1.905,-2.718; 2 -1.27,-2.718; 3 -0.635,-2.718; 4 0,-2.718; 5 0.635,-2.718; 6 1.27,-2.718; 7 1.905,-2.718; 8 1.905,2.718; 9 1.27,2.718; 10 0.635,2.718; 11 0,2.718; 12 -0.635,2.718; 13 -1.27,2.718; 14 -1.905,2.718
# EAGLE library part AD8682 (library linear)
Dual Low Power, High Speed JFET Operational Amplifiers Source: http://www.analog.com/UploadedFiles/Data_Sheets/AD8682_8684.pdf

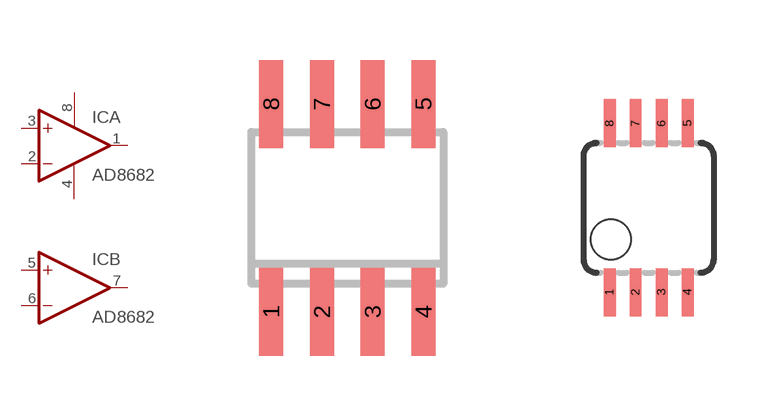
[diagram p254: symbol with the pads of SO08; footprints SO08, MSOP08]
Designator prefix IC; gates A=OPAMP B=OPAMP P=PWR+-

## AD8682R  [SO08]
1  A:OUT  out
2  A:-IN  in
3  A:+IN  in
4  P:V-  pwr
5  B:+IN  in
6  B:-IN  in
7  B:OUT  out
8  P:V+  pwr

## AD8682RM  [MSOP08]
Pads as for SO08

## Footprint SO08 (pad centres in mm)
Small Outline Package 8 NS Package M08A
smd 0.6 x 2.2: 1 -1.905,-2.6; 2 -0.635,-2.6; 3 0.635,-2.6; 4 1.905,-2.6; 5 1.905,2.6; 6 0.635,2.6; 7 -0.635,2.6; 8 -1.905,2.6

## Footprint MSOP08 (pad centres in mm)
Mini Small Outline Package
smd 0.3 x 1.2: 1 -0.976,-2.113; 2 -0.326,-2.113; 3 0.324,-2.113; 4 0.974,-2.113; 5 0.974,2.112; 6 0.324,2.112; 7 -0.326,2.112; 8 -0.976,2.112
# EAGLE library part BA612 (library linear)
5-channel high current driver Source: http://www.classiccmp.org/rtellason/chipdata/ba612.pdf

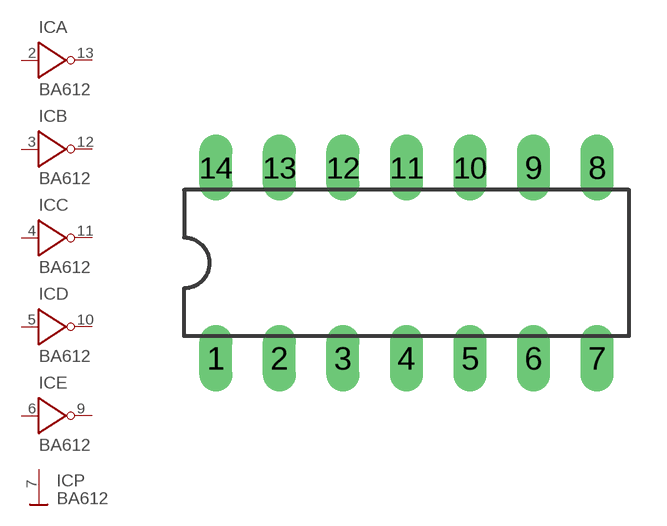
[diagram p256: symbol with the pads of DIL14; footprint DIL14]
Designator prefix IC; gates A=INVERTER B=INVERTER C=INVERTER D=INVERTER E=INVERTER P=GND

## BA612  [DIL14]
2  A:I  in
3  B:I  in
4  C:I  in
5  D:I  in
6  E:I  in
7  P:O  in
9  E:O  in
10  D:O  in
11  C:O  in
12  B:O  in
13  A:O  in

## Footprint DIL14 (pad centres in mm)
Dual In Line Package
drill 0.813 long: 1 -7.62,-3.81; 2 -5.08,-3.81; 3 -2.54,-3.81; 4 0,-3.81; 5 2.54,-3.81; 6 5.08,-3.81; 7 7.62,-3.81; 8 7.62,3.81; 9 5.08,3.81; 10 2.54,3.81; 11 0,3.81; 12 -2.54,3.81; 13 -5.08,3.81; 14 -7.62,3.81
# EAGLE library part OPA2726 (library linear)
Very Low Noise, High-Speed, 12V CMOS Operational Amplifier with Shutdown Source: http://focus.ti.com/lit/ds/symlink/opa725.pdf

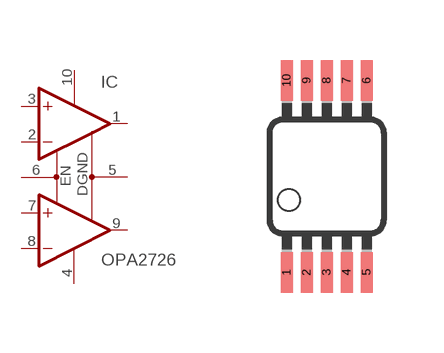
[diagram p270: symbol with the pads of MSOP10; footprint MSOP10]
Designator prefix IC

## OPA2726  [MSOP10]
1  OUTA  out
2  -INA  in
3  +INA  in
4  V-  pwr
5  DGND  in
6  EN  in
7  +INB  in
8  -INB  in
9  OUTB  out
10  V+  pwr

## Footprint MSOP10 (pad centres in mm)
10 Lead MSOP Package NS Package Number MUB10A Source: http://cache.national.com/ds/LM/LM5030.pdf
smd 0.3 x 1.02: 1 -1,-2.4; 2 -0.5,-2.4; 3 0,-2.4; 4 0.5,-2.4; 5 1,-2.4; 6 1,2.4; 7 0.5,2.4; 8 0,2.4; 9 -0.5,2.4; 10 -1,2.4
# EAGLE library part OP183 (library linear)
5 MHz Single-Supply Operational Amplifier Source: http://www.analog.com/static/imported-files/data_sheets/OP183.pdf

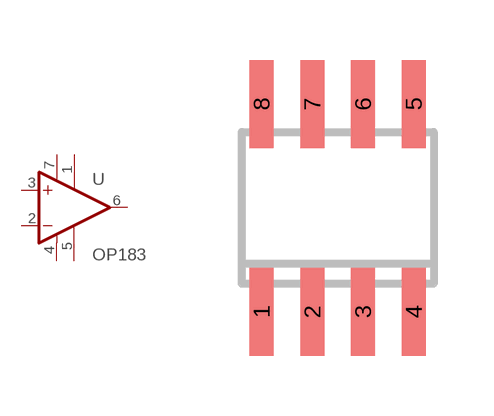
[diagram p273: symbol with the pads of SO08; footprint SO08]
Designator prefix -

## OP183S  [SO08]
1  OFF1  pas
2  -IN  in
3  +IN  in
4  V-  pwr
5  OFF2  pas
6  OUT  out
7  V+  pwr

## Footprint SO08 (pad centres in mm)
Small Outline Package 8 NS Package M08A
smd 0.6 x 2.2: 1 -1.905,-2.6; 2 -0.635,-2.6; 3 0.635,-2.6; 4 1.905,-2.6; 5 1.905,2.6; 6 0.635,2.6; 7 -0.635,2.6; 8 -1.905,2.6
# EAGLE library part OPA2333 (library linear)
DUAL 1.8V, microPOWER CMOS OPERATIONAL AMPLIFIERS Zerø-Drift Series Source: Texas Instruments (Burr-Brown) .. U11 opa333 Operational Amp.pdf

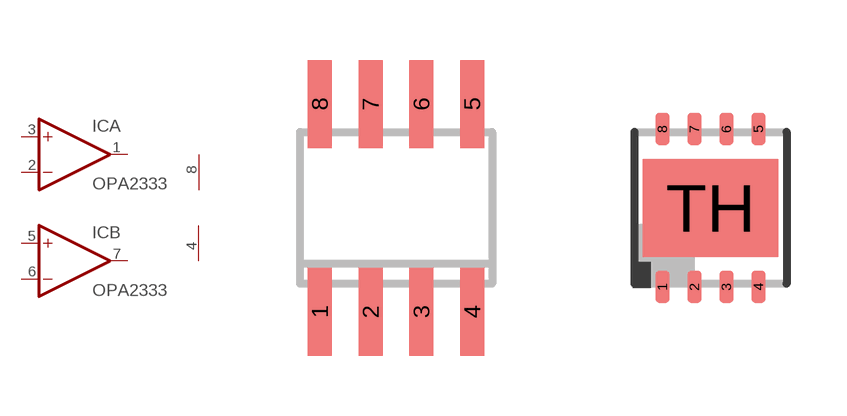
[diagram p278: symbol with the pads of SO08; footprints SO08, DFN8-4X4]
Designator prefix IC; gates A=OPAMP B=OPAMP P=PWR+-

## OPA2333D  [SO08]
1  A:OUT  out
2  A:-IN  in
3  A:+IN  in
4  P:V-  pwr
5  B:+IN  in
6  B:-IN  in
7  B:OUT  out
8  P:V+  pwr

## OPA2333DRB  [DFN8-4X4]
Pads as for SO08

## OPA2333DGK  [MSOP08]
Pads as for SO08

## Footprint SO08 (pad centres in mm)
Small Outline Package 8 NS Package M08A
smd 0.6 x 2.2: 1 -1.905,-2.6; 2 -0.635,-2.6; 3 0.635,-2.6; 4 1.905,-2.6; 5 1.905,2.6; 6 0.635,2.6; 7 -0.635,2.6; 8 -1.905,2.6

## Footprint DFN8-4X4 (pad centres in mm)
DFN8 4x4 mm DRM (S-PDSO-N8) Source: opa277.pdf
smd 0.35 x 0.8: 1 -1.2,-1.975; 2 -0.4,-1.975; 3 0.4,-1.975; 4 1.2,-1.975; 5 1.2,1.975; 6 0.4,1.975; 7 -0.4,1.975; 8 -1.2,1.975
smd 3.38 x 2.45: TH 0,0

## Footprint MSOP08 (pad centres in mm)
Mini Small Outline Package
smd 0.3 x 1.2: 1 -0.976,-2.113; 2 -0.326,-2.113; 3 0.324,-2.113; 4 0.974,-2.113; 5 0.974,2.112; 6 0.324,2.112; 7 -0.326,2.112; 8 -0.976,2.112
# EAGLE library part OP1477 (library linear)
Precision Low Noise, Low Input Bias Current Operational Amplifiers Source: OP1177_2177_4177.pdf

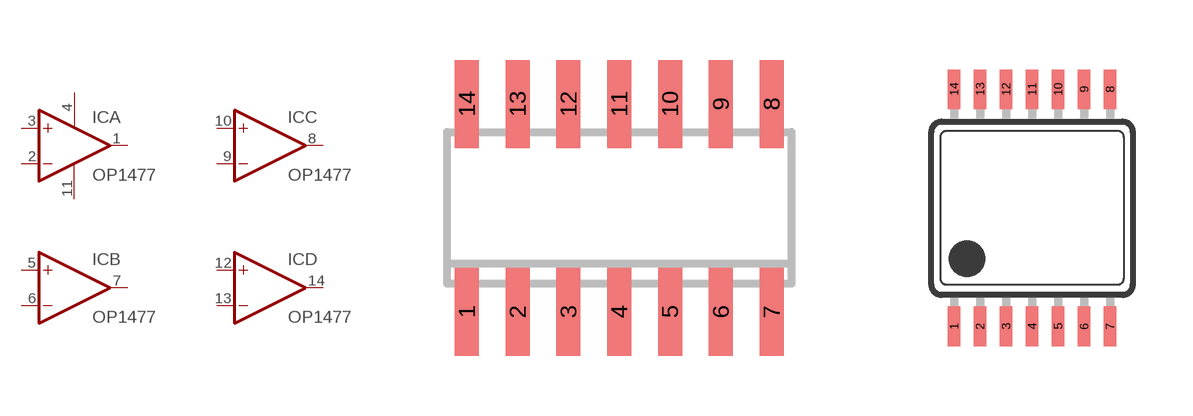
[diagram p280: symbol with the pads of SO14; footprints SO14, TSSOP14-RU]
Designator prefix IC; gates A=OPAMP B=OPAMP C=OPAMP D=OPAMP P=PWR+-

## OP1477R  [SO14]
1  A:OUT  out
2  A:-IN  in
3  A:+IN  in
4  P:V+  pwr
5  B:+IN  in
6  B:-IN  in
7  B:OUT  out
8  C:OUT  out
9  C:-IN  in
10  C:+IN  in
11  P:V-  pwr
12  D:+IN  in
13  D:-IN  in
14  D:OUT  out

## OP1477RU  [TSSOP14-RU]
Pads as for SO14

## Footprint SO14 (pad centres in mm)
Small Outline Package 14
smd 0.6 x 2.2: 1 -3.81,-2.6; 2 -2.54,-2.6; 3 -1.27,-2.6; 4 0,-2.6; 5 1.27,-2.6; 6 2.54,-2.6; 7 3.81,-2.6; 8 3.81,2.6; 9 2.54,2.6; 10 1.27,2.6; 11 0,2.6; 12 -1.27,2.6; 13 -2.54,2.6; 14 -3.81,2.6

## Footprint TSSOP14-RU (pad centres in mm)
14-Lead Thin Shrink Small Outline Package [TSSOP] (RU-14) Source: www.analog.com .. OP1177_2177_4177.pdf
smd 0.305 x 0.991: 1 -1.95,-2.968; 2 -1.3,-2.968; 3 -0.65,-2.968; 4 0,-2.968; 5 0.65,-2.968; 6 1.3,-2.968; 7 1.95,-2.968; 8 1.95,2.968; 9 1.3,2.968; 10 0.65,2.968; 11 0,2.968; 12 -0.65,2.968; 13 -1.3,2.968; 14 -1.95,2.968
